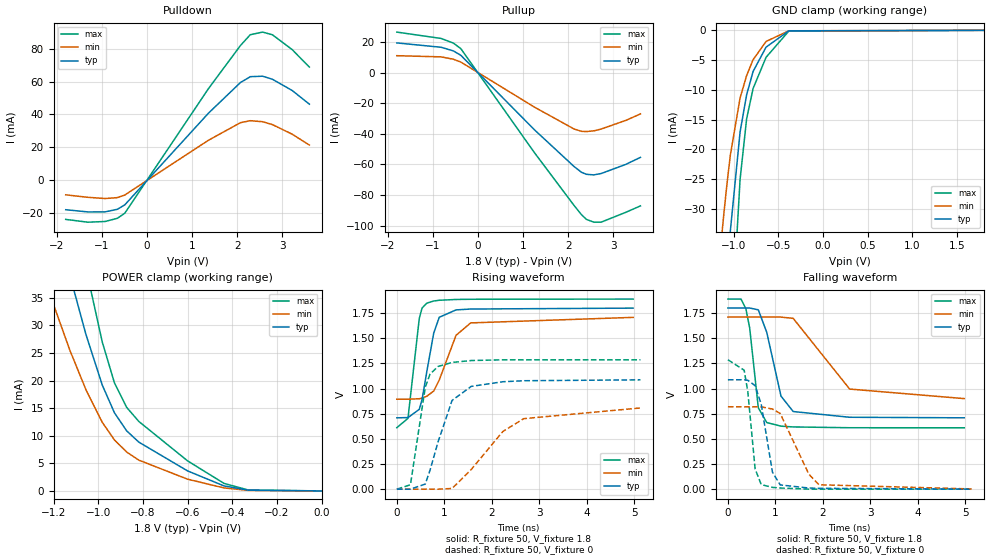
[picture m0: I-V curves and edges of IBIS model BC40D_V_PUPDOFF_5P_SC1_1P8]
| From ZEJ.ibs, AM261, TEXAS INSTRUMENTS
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[Model]   BC40D_V_PUPDOFF_5P_SC1_1P8
Model_type   I/O
Polarity   Non-Inverting
Enable   Active-Low
Vinl =  0.63
Vinh =  1.17
Cref =  15pF
Rref =  100.0000M
Vref =  0V
Vmeas =  0.9
C_comp   2.233931p   2.204415p   2.290246p
|[Input load] weak_pupdoff
|[Output drive] slow
|[supplytol] 5
|[temp] ind
[Model Spec]
Vinl   0.63   0.5985   0.6615
Vinh   1.17   1.1115   1.2285
[Temperature Range]   25   125   -40
[Voltage Range]   1.8   1.71   1.89
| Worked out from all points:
|   slope of the pulldown table from 0 to 0.27 V, typ, clamps not added: 32.2 ohm
|   slope of the pullup table from 0 to 0.27 V, typ, clamps not added: 32.6 ohm
|   GND clamp passes 1 mA (typ) near -0.53 V on its own axis
|   POWER clamp passes 1 mA (typ) near -0.44 V on its own axis
|   rising waveform, R_fixture 50, V_fixture 1.8: 20-80 % time 246ps typ, 396ps min, 169ps max; typ from 0.709 V to 1.8 V
|   rising waveform, R_fixture 50, V_fixture 0: 20-80 % time 429ps typ, 920ps min, 245ps max; typ from 0 V to 1.09 V
|   falling waveform, R_fixture 50, V_fixture 1.8: 20-80 % time 308ps typ, 718ps min, 171ps max; typ from 1.8 V to 0.709 V
|   falling waveform, R_fixture 50, V_fixture 0: 20-80 % time 226ps typ, 430ps min, 154ps max; typ from 1.09 V to 0 V
| Nom Voltages:
|   VDD=1.1, VDDS=1.8, VDDS18=1.8, ESD_BIASFET=0, VSS=0, VSSS=0
| Min Voltages:
|   VDD=1.045, VDDS=1.71, VDDS18=1.71, ESD_BIASFET=0, VSS=0, VSSS=0
| Max Voltages:
|   VDD=1.16, VDDS=1.89, VDDS18=1.89, ESD_BIASFET=0, VSS=0, VSSS=0
[POWER_clamp]
|   voltage   I(typ)   I(min)   I(max)
-1.8V     158.8mA    112.5mA    219.7mA
-1.255V   59.93mA    39.99mA    84.86mA
-1.127V   39.08mA    25.5mA     55.75mA
-1.055V   28.36mA    18.34mA    40.41mA
-981.8mV  19.18mA    12.43mA    26.98mA
-927.3mV  14.16mA    9.239mA    19.58mA
-872.7mV  10.89mA    7.049mA    15.14mA
-818.2mV  8.843mA    5.579mA    12.59mA
-600mV    3.63mA     2.128mA    5.45mA
-436.4mV  903.9uA    539uA      1.358mA
-327.3mV  138.2uA    94.87uA    160.3uA
0V        19.3nA     133.7nA    230.3nA
[Pulldown]
|   voltage   I(typ)   I(min)   I(max)
-1.8V     -17.92mA   -8.85mA    -23.8mA
-1.309V   -19.26mA   -10.37mA   -25.5mA
-927.3mV  -19.22mA   -11.12mA   -25.08mA
-654.5mV  -17.65mA   -10.56mA   -23.13mA
-490.9mV  -14.97mA   -8.985mA   -20.05mA
1.364V    40.78mA    24.32mA    55.7mA
2.073V    59.41mA    35mA       81.91mA
2.291V    62.96mA    36.2mA     88.48mA
2.564V    63.25mA    35.58mA    90.07mA
2.782V    61.38mA    33.82mA    88.42mA
3.218V    54.59mA    28.02mA    79.45mA
3.6V      46.26mA    21.39mA    68.79mA
[Pullup]
|   voltage   I(typ)   I(min)   I(max)
-1.8V     19.42mA    11.07mA    26.5mA
-818.2mV  16.58mA    10.3mA     22.34mA
-545.5mV  14.19mA    8.748mA    19.29mA
-381.8mV  11.34mA    6.915mA    15.7mA
1.255V    -37.51mA   -22.64mA   -52.53mA
2.127V    -61.34mA   -36.82mA   -86.78mA
2.291V    -65.12mA   -38.38mA   -92.82mA
2.4V      -66.46mA   -38.53mA   -95.91mA
2.564V    -66.86mA   -38.08mA   -97.75mA
2.727V    -65.99mA   -36.9mA    -97.78mA
3.273V    -60.01mA   -31.26mA   -91.34mA
3.6V      -55.4mA    -26.98mA   -87.12mA
[GND_clamp]
|   voltage   I(typ)   I(min)   I(max)
-1.8V     -270.2mA   -170.2mA   -430.1mA
-1.255V   -91.66mA   -55.91mA   -148.4mA
-1.145V   -59.91mA   -36.45mA   -97.09mA
-1.109V   -50.48mA   -30.83mA   -81.55mA
-1.073V   -41.73mA   -25.65mA   -67.05mA
-1.036V   -33.66mA   -20.92mA   -53.59mA
-927.3mV  -17.07mA   -11.35mA   -25.04mA
-854.5mV  -10.86mA   -7.617mA   -14.91mA
-781.8mV  -6.919mA   -4.945mA   -9.771mA
-636.4mV  -2.823mA   -1.868mA   -4.529mA
-381.8mV  -84.73uA   -78.82uA   -126.1uA
1.8V      19.3nA     350.9nA    215.8nA
[Ramp]
| variable   typ   min   max
dV/dt_f 0.66170167/0.31099078n 0.49657778/0.73394202n 0.77361898/0.17271731n
dV/dt_r 0.65944933/0.43266271n 0.50305793/0.9625316n 0.77800654/0.24641056n
R_load = 50
[Rising Waveform]
R_fixture = 50
V_fixture = 1.8
V_fixture_min = 1.71
V_fixture_max = 1.89
|   time   V(typ)   V(min)   V(max)
0s        709.3mV    894.5mV    611.4mV
234.6ps   711.5mV    894.5mV    703.8mV
472.5ps   793.4mV    898.9mV    1.696V
530.6ps   889.7mV    906mV      1.8V
629.4ps   1.164V     923.1mV    1.849V
776.9ps   1.552V     975.4mV    1.871V
893ps     1.709V     1.085V     1.878V
1.246ns   1.782V     1.529V     1.886V
1.554ns   1.791V     1.653V     1.888V
4.974ns   1.8V       1.708V     1.89V
[Rising Waveform]
R_fixture = 50
V_fixture = 0
V_fixture_min = 0
V_fixture_max = 0
|   time   V(typ)   V(min)   V(max)
0s        0V         0V         0V
286.6ps   0V         0V         43.73mV
599.1ps   50.7mV     0V         1.014V
699.4ps   189mV      0V         1.144V
867.6ps   469.4mV    0V         1.22V
1.163ns   882.5mV    6.887mV    1.26V
1.567ns   1.022V     196.1mV    1.279V
2.232ns   1.068V     573.7mV    1.286V
2.671ns   1.078V     701.1mV    1.286V
5.128ns   1.087V     807.5mV    1.286V
[Falling Waveform]
R_fixture = 50
V_fixture = 1.8
V_fixture_min = 1.71
V_fixture_max = 1.89
|   time   V(typ)   V(min)   V(max)
0s        1.8V       1.71V      1.889V
275ps     1.8V       1.71V      1.889V
378.3ps   1.8V       1.71V      1.793V
458.3ps   1.8V       1.71V      1.601V
639.6ps   1.782V     1.71V      808.7mV
817.6ps   1.558V     1.71V      661.9mV
1.117ns   924.6mV    1.71V      626.1mV
1.374ns   771.3mV    1.697V     618.4mV
2.562ns   714.5mV    994.7mV    610.4mV
4.974ns   709mV      899.8mV    610mV
[Falling Waveform]
R_fixture = 50
V_fixture = 0
V_fixture_min = 0
V_fixture_max = 0
|   time   V(typ)   V(min)   V(max)
0s        1.087V     818.1mV    1.286V
342.4ps   1.087V     818.1mV    1.182V
418.5ps   1.082V     818.1mV    969.6mV
572.1ps   1.029V     818.1mV    202.3mV
701ps     843.3mV    818.1mV    45.39mV
938.3ps   167.4mV    795.8mV    17.73mV
1.101ns   42.19mV    751.8mV    11.59mV
1.704ns   11.22mV    148.3mV    0V
1.916ns   8.516mV    43.66mV    0V
5.128ns   0V         2.183mV    0V
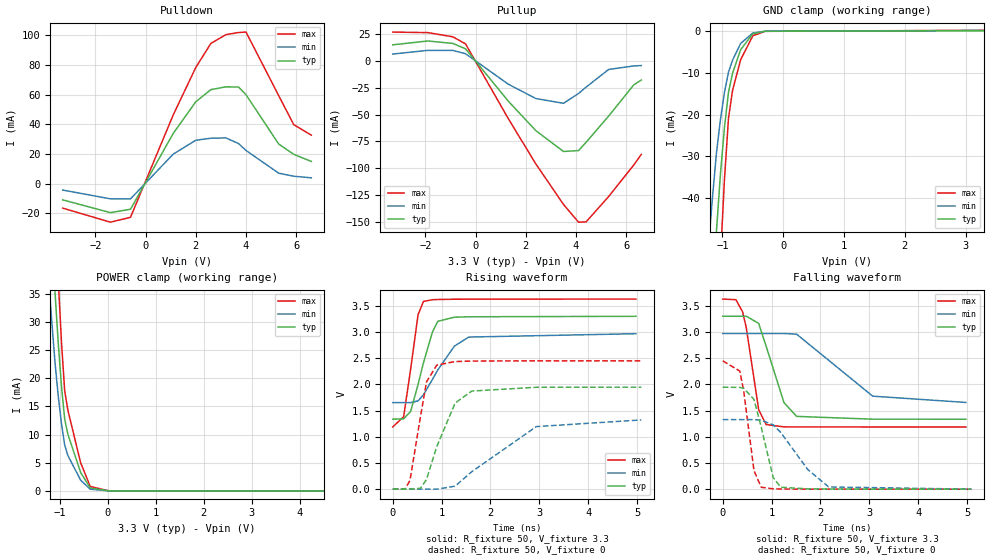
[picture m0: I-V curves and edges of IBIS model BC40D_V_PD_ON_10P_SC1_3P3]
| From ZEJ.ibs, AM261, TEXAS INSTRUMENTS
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[Model]   BC40D_V_PD_ON_10P_SC1_3P3
Model_type   I/O
Polarity   Non-Inverting
Enable   Active-Low
Vinl =  0.8V
Vinh =  2V
Cref =  15pF
Rref =  100.0000M
Vref =  0V
Vmeas =  1.65
C_comp   2.059994p   1.912853p   2.135747p
|[Input load] weak_pd_on
|[Output drive] slow
|[supplytol] 10
|[temp] ind
[Model Spec]
Vinl   0.8V   0.8V   0.8V
Vinh   2V   2V   2V
[Temperature Range]   25   125   -40
[Voltage Range]   3.3   2.97   3.63
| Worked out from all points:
|   slope of the pulldown table from 0 to 0.495 V, typ, clamps not added: 31.8 ohm
|   slope of the pullup table from 0 to 0.495 V, typ, clamps not added: 33.8 ohm
|   GND clamp passes 1 mA (typ) near -0.52 V on its own axis
|   POWER clamp passes 1 mA (typ) near -0.42 V on its own axis
|   rising waveform, R_fixture 50, V_fixture 3.3: 20-80 % time 334ps typ, 532ps min, 208ps max; typ from 1.33 V to 3.3 V
|   rising waveform, R_fixture 50, V_fixture 0: 20-80 % time 466ps typ, 1.07ns min, 244ps max; typ from 0 V to 1.95 V
|   falling waveform, R_fixture 50, V_fixture 3.3: 20-80 % time 385ps typ, 931ps min, 233ps max; typ from 3.3 V to 1.33 V
|   falling waveform, R_fixture 50, V_fixture 0: 20-80 % time 293ps typ, 644ps min, 201ps max; typ from 1.95 V to 0 V
| Nom Voltages:
|   VDD=1.1001, VDDS=3.3, VDDS18=1.8, ESD_BIASFET=0, VSS=0, VSSS=0
| Min Voltages:
|   VDD=0.99, VDDS=2.97, VDDS18=1.62, ESD_BIASFET=0, VSS=0, VSSS=0
| Max Voltages:
|   VDD=1.21, VDDS=3.63, VDDS18=1.98, ESD_BIASFET=0, VSS=0, VSSS=0
[POWER_clamp]
|   voltage   I(typ)   I(min)   I(max)
-3.3V     446.9mA    419.5mA    603.9mA
-1.233V   56.59mA    37.53mA    80.37mA
-1.167V   45.68mA    29.91mA    65.17mA
-1.1V     35.14mA    22.68mA    50.36mA
-1.033V   26.13mA    16.78mA    37.31mA
-966.7mV  18.67mA    11.95mA    26.46mA
-900mV    12.76mA    8.172mA    17.82mA
-833.3mV  10.07mA    6.29mA     14.35mA
-566.7mV  3.276mA    1.904mA    4.983mA
-366.7mV  519.9uA    307.2uA    792.3uA
33.33mV   0A         0A         0A
6.6V      0A         0A         0A
[Pulldown]
|   voltage   I(typ)   I(min)   I(max)
-3.3V     -10.93mA   -4.311mA   -16.48mA
-1.4V     -19.53mA   -10.23mA   -25.96mA
-600mV    -17.23mA   -10.26mA   -22.66mA
1.1V      33.82mA    19.89mA    46.25mA
2V        55.14mA    29.24mA    78.29mA
2.6V      63.35mA    30.61mA    94.44mA
3.2V      65.21mA    30.81mA    100.4mA
3.7V      65.09mA    27.02mA    101.8mA
4V        59.92mA    22.37mA    102.1mA
5.3V      26.68mA    7.058mA    59.31mA
5.9V      19.77mA    5.007mA    39.76mA
6.6V      14.97mA    3.923mA    32.7mA
[Pullup]
|   voltage   I(typ)   I(min)   I(max)
-3.3V     15.12mA    6.498mA    27.02mA
-1.9V     18.73mA    9.943mA    26.53mA
-900mV    16.4mA     9.888mA    22.58mA
-400mV    11.39mA    6.786mA    15.98mA
1.3V      -37.44mA   -21.62mA   -53.74mA
2.4V      -65.08mA   -35.06mA   -96.18mA
3.5V      -84.52mA   -39.53mA   -134mA
4.1V      -83.69mA   -30.35mA   -150.6mA
4.4V      -75.99mA   -24.42mA   -150.3mA
5.3V      -51.41mA   -7.872mA   -126.6mA
6.3V      -22.29mA   -4.606mA   -97.15mA
6.6V      -17.71mA   -4.277mA   -87.2mA
[GND_clamp]
|   voltage   I(typ)   I(min)   I(max)
-3.3V     -787.2mA   -607.8mA   -1.235A
-1.233V   -85.66mA   -52.14mA   -138.8mA
-1.167V   -66.47mA   -40.37mA   -107.7mA
-1.1V     -48.25mA   -29.37mA   -77.99mA
-1.033V   -34.28mA   -21.19mA   -54.56mA
-966.7mV  -23.07mA   -14.67mA   -35.51mA
-900mV    -14.62mA   -9.792mA   -20.84mA
-833.3mV  -10.07mA   -6.938mA   -14.17mA
-700mV    -4.435mA   -2.939mA   -6.836mA
-500mV    -641.2uA   -454.5uA   -1.12mA
-300mV    -31.62uA   -32.73uA   -44.27uA
3.3V      108.6uA    159.4uA    198.5uA
[Ramp]
| variable   typ   min   max
dV/dt_f  1.1800539/0.38506764n 0.79469436/0.93858809n  1.4663953/0.23379182n
dV/dt_r  1.1731734/0.46682563n 0.80227934/1.080283n   1.4754285/0.24457461n
R_load = 50
[Rising Waveform]
R_fixture = 50
V_fixture = 3.3
V_fixture_min = 2.97
V_fixture_max = 3.63
|   time   V(typ)   V(min)   V(max)
0s        1.335V     1.651V     1.187V
223.4ps   1.341V     1.651V     1.381V
367.1ps   1.484V     1.651V     2.291V
518.6ps   1.998V     1.684V     3.33V
630.3ps   2.415V     1.802V     3.582V
810.3ps   2.992V     2.09V      3.614V
921.6ps   3.202V     2.274V     3.619V
1.262ns   3.281V     2.729V     3.624V
1.555ns   3.289V     2.902V     3.625V
4.974ns   3.298V     2.966V     3.627V
[Rising Waveform]
R_fixture = 50
V_fixture = 0
V_fixture_min = 0
V_fixture_max = 0
|   time   V(typ)   V(min)   V(max)
0s        0V         0V         0V
249.1ps   0V         0V         0V
353.3ps   0V         0V         165.9mV
568ps     16.56mV    0V         1.387V
691.3ps   186.6mV    0V         2.047V
902.7ps   815.8mV    0V         2.368V
1.276ns   1.642V     57.01mV    2.435V
1.617ns   1.872V     333.2mV    2.444V
2.938ns   1.944V     1.194V     2.449V
5.085ns   1.946V     1.321V     2.449V
[Falling Waveform]
R_fixture = 50
V_fixture = 3.3
V_fixture_min = 2.97
V_fixture_max = 3.63
|   time   V(typ)   V(min)   V(max)
0s        3.298V     2.969V     3.626V
269.8ps   3.298V     2.969V     3.614V
406.5ps   3.298V     2.969V     3.383V
483ps     3.298V     2.969V     3.075V
735.8ps   3.162V     2.969V     1.517V
887.5ps   2.728V     2.969V     1.233V
1.253ns   1.652V     2.969V     1.188V
1.512ns   1.388V     2.956V     1.187V
3.068ns   1.335V     1.774V     1.186V
4.974ns   1.334V     1.654V     1.186V
[Falling Waveform]
R_fixture = 50
V_fixture = 0
V_fixture_min = 0
V_fixture_max = 0
|   time   V(typ)   V(min)   V(max)
0s        1.945V     1.327V     2.448V
348.9ps   1.941V     1.327V     2.253V
428.9ps   1.924V     1.327V     1.879V
639.9ps   1.712V     1.327V     355.4mV
786.5ps   1.188V     1.317V     36.13mV
1.032ns   222.4mV    1.227V     6.608mV
1.187ns   36.69mV    1.082V     3.214mV
1.739ns   6.423mV    374.9mV    0V
2.167ns   3.049mV    42.27mV    0V
5.085ns   0V         0V         0V
